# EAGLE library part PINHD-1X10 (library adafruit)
Pin header 1x10 0.1" spacing With round pins

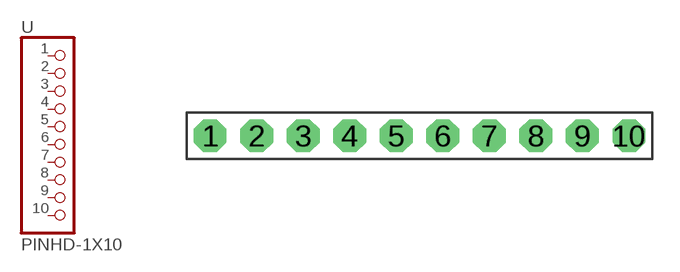
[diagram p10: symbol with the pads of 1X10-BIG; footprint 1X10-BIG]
Designator prefix -

## PINHD-1X10  [1X10-BIG]
1  1  pas
2  2  pas
3  3  pas
4  4  pas
5  5  pas
6  6  pas
7  7  pas
8  8  pas
9  9  pas
10  10  pas

## Footprint 1X10-BIG (pad centres in mm)
drill 1.016 pad 1.778 octagon: 1 -11.43,0; 2 -8.89,0; 3 -6.35,0; 4 -3.81,0; 5 -1.27,0; 6 1.27,0; 7 3.81,0; 8 6.35,0; 9 8.89,0; 10 11.43,0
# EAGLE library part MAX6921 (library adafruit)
MAX6921 76V VFD driver in TSSOP and PLCC. Can be cascaded, talk to it via SPI

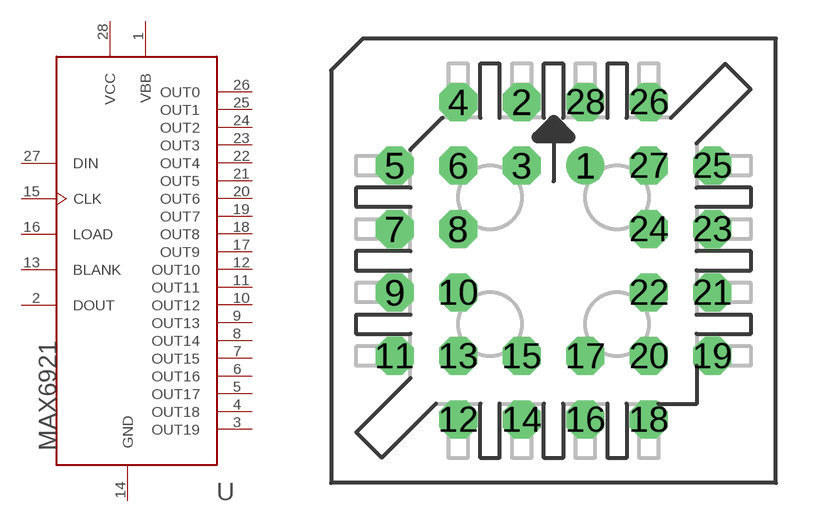
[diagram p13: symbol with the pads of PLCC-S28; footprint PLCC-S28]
Designator prefix -

## MAX6921  [PLCC-S28]
1  VBB  sup
2  DOUT  out
3  OUT19  out
4  OUT18  out
5  OUT17  out
6  OUT16  out
7  OUT15  out
8  OUT14  out
9  OUT13  out
10  OUT12  out
11  OUT11  out
12  OUT10  out
13  BLANK  in
14  GND  sup
15  CLK  in
16  LOAD  in
17  OUT9  out
18  OUT8  out
19  OUT7  out
20  OUT6  out
21  OUT5  out
22  OUT4  out
23  OUT3  out
24  OUT2  out
25  OUT1  out
26  OUT0  out
27  DIN  in
28  VCC  pwr

## Footprint PLCC-S28 (pad centres in mm)
Plastic Leaded Chip Carrier Socked
drill 0.813 pad 1.524 round: 1 1.27,3.81
drill 0.813 pad 1.524 octagon: 2 -1.27,6.35; 3 -1.27,3.81; 4 -3.81,6.35; 5 -6.35,3.81; 6 -3.81,3.81; 7 -6.35,1.27; 8 -3.81,1.27; 9 -6.35,-1.27; 10 -3.81,-1.27; 11 -6.35,-3.81; 12 -3.81,-6.35; 13 -3.81,-3.81; 14 -1.27,-6.35; 15 -1.27,-3.81; 16 1.27,-6.35; 17 1.27,-3.81; 18 3.81,-6.35; 19 6.35,-3.81; 20 3.81,-3.81; 21 6.35,-1.27; 22 3.81,-1.27; 23 6.35,1.27; 24 3.81,1.27; 25 6.35,3.81; 26 3.81,6.35; 27 3.81,3.81; 28 1.27,6.35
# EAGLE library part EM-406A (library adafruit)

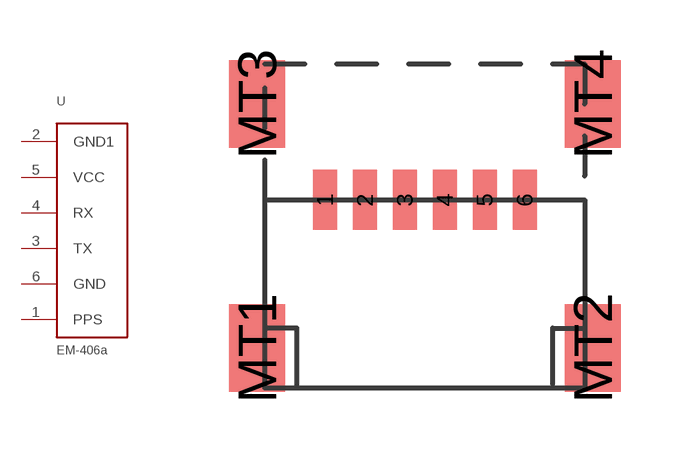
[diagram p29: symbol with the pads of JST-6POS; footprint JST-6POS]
Designator prefix -

## EM-406A  [JST-6POS]
1  PPS  out
2  GND1  sup
3  TX  out
4  RX  in
5  VCC  sup
6  GND  sup

## Footprint JST-6POS (pad centres in mm)
smd 0.6 x 1.5: 1 -2.5,4.7; 2 -1.5,4.7; 3 -0.5,4.7; 4 0.5,4.7; 5 1.5,4.7; 6 2.5,4.7
smd 1.4 x 2.2: MT1 -4.2,1; MT2 4.2,1; MT3 -4.2,7.1; MT4 4.2,7.1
